One B-rep face of a CAD part: STEP entity #408.
In plain terms, the planar face has unit normal (1, 0, 0).
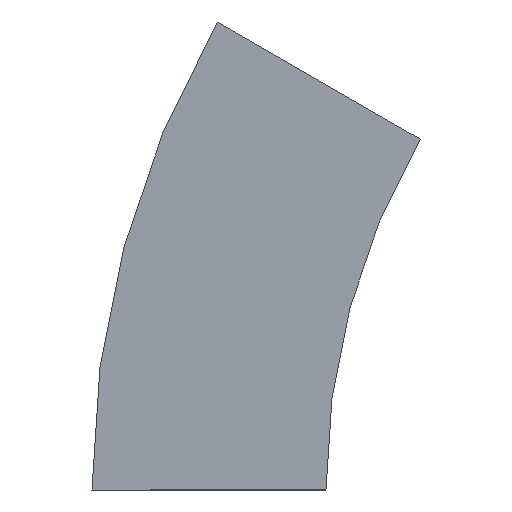
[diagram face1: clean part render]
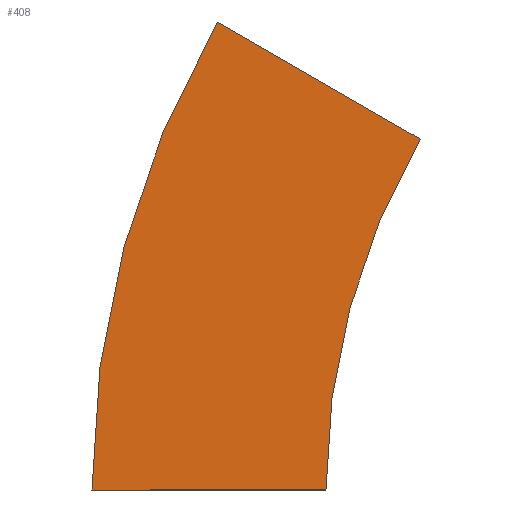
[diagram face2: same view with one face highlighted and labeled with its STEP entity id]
Its self-contained STEP definition (entity closure, numbers rounded to 3 decimals):
#4 = DIRECTION ( 'NONE',  ( 0., 1., 0. ) ) ;
#8 = EDGE_CURVE ( 'NONE', #481, #137, #135, .T. ) ;
#49 = EDGE_CURVE ( 'NONE', #293, #310, #271, .T. ) ;
#73 = DIRECTION ( 'NONE',  ( 0., 1., 0. ) ) ;
#109 = CARTESIAN_POINT ( 'NONE',  ( 0., 0., 0. ) ) ;
#116 = EDGE_CURVE ( 'NONE', #310, #137, #491, .T. ) ;
#118 = CARTESIAN_POINT ( 'NONE',  ( 0., 46.41, 200. ) ) ;
#135 = LINE ( 'NONE', #507, #370 ) ;
#137 = VERTEX_POINT ( 'NONE', #118 ) ;
#145 = CARTESIAN_POINT ( 'NONE',  ( 0., -300., 0. ) ) ;
#163 = DIRECTION ( 'NONE',  ( 0., 1., 0. ) ) ;
#205 = AXIS2_PLACEMENT_3D ( 'NONE', #145, #327, #73 ) ;
#210 = DIRECTION ( 'NONE',  ( 0., 0., -1. ) ) ;
#220 = ORIENTED_EDGE ( 'NONE', *, *, #353, .F. ) ;
#247 = CARTESIAN_POINT ( 'NONE',  ( 0., 0., 0. ) ) ;
#260 = ORIENTED_EDGE ( 'NONE', *, *, #49, .T. ) ;
#271 = LINE ( 'NONE', #277, #354 ) ;
#277 = CARTESIAN_POINT ( 'NONE',  ( 0., 0., 0. ) ) ;
#293 = VERTEX_POINT ( 'NONE', #109 ) ;
#298 = DIRECTION ( 'NONE',  ( 1., 0., 0. ) ) ;
#309 = DIRECTION ( 'NONE',  ( 0., 0.866, 0.5 ) ) ;
#310 = VERTEX_POINT ( 'NONE', #407 ) ;
#327 = DIRECTION ( 'NONE',  ( 1., 0., 0. ) ) ;
#330 = FACE_OUTER_BOUND ( 'NONE', #388, .T. ) ;
#332 = AXIS2_PLACEMENT_3D ( 'NONE', #247, #411, #210 ) ;
#353 = EDGE_CURVE ( 'NONE', #293, #481, #443, .T. ) ;
#354 = VECTOR ( 'NONE', #4, 1000. ) ;
#368 = PLANE ( 'NONE',  #332 ) ;
#369 = AXIS2_PLACEMENT_3D ( 'NONE', #372, #298, #163 ) ;
#370 = VECTOR ( 'NONE', #309, 1000. ) ;
#372 = CARTESIAN_POINT ( 'NONE',  ( 0., -300., 0. ) ) ;
#388 = EDGE_LOOP ( 'NONE', ( #425, #464, #220, #260 ) ) ;
#407 = CARTESIAN_POINT ( 'NONE',  ( 0., 100., 0. ) ) ;
#408 = ADVANCED_FACE ( 'NONE', ( #330 ), #368, .T. ) ;
#411 = DIRECTION ( 'NONE',  ( 1., 0., 0. ) ) ;
#425 = ORIENTED_EDGE ( 'NONE', *, *, #116, .T. ) ;
#443 = CIRCLE ( 'NONE', #205, 300. ) ;
#464 = ORIENTED_EDGE ( 'NONE', *, *, #8, .F. ) ;
#481 = VERTEX_POINT ( 'NONE', #536 ) ;
#491 = CIRCLE ( 'NONE', #369, 400. ) ;
#507 = CARTESIAN_POINT ( 'NONE',  ( 0., -40.192, 150. ) ) ;
#536 = CARTESIAN_POINT ( 'NONE',  ( 0., -40.192, 150. ) ) ;
